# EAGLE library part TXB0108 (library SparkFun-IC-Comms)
8-Bit Bi-Directional Level Shifter Warning! Do not use for open-drain (I2C) signals. Consider TXS0108 1.2V-3.6V (VCCA) to 1.65V-5.5V (VCCB) bi-directional level shifter with auto direction sensing. Max data rate - VCCA 1.2V: 20Mbps (50ns), VCCA 3.3V: 100Mbps (10ns) Digikey: 296-27217-1-ND (20-UFDFN) SparkFun Products SparkFun GPS Logger Shield (GPS-13750) SparkFun Block for Intel® Edison - microSD (DEV-13041) SparkFun Block for Intel® Edison - Dual H-Bridge (DEV-13043) SparkFun Block for Intel® Edison - GPIO (DEV-13038) SparkFun Block for Intel® Edison - Raspberry Pi B (DEV-13044)

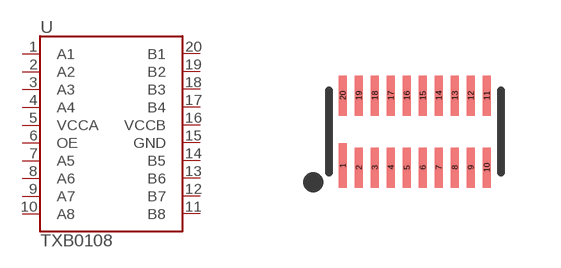
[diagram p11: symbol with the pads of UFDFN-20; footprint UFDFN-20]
Designator prefix U

## TXB0108 (PROD_ID: IC-12292; VALUE: TXB0108DQSR)  [UFDFN-20]
1  A1
2  A2
3  A3
4  A4
5  VCCA
6  OE
7  A5
8  A6
9  A7
10  A8
11  B8
12  B7
13  B6
14  B5
15  GND
16  VCCB
17  B4
18  B3
19  B2
20  B1

## Footprint UFDFN-20 (pad centres in mm)
UFDFN-20 Specifications: Pin count: 20 Example device(s): TXB0108
smd 0.2 x 1.1: 1 -1.8,-0.85
smd 0.2 x 1: 2 -1.4,-0.9; 3 -1,-0.9; 4 -0.6,-0.9; 5 -0.2,-0.9; 6 0.2,-0.9; 7 0.6,-0.9; 8 1,-0.9; 9 1.4,-0.9; 10 1.8,-0.9; 11 1.8,0.9; 12 1.4,0.9; 13 1,0.9; 14 0.6,0.9; 15 0.2,0.9; 16 -0.2,0.9; 17 -0.6,0.9; 18 -1,0.9; 19 -1.4,0.9; 20 -1.8,0.9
